VERSION 5.8 ;
BUSBITCHARS "[]" ;
DIVIDERCHAR "/" ;
UNITS
  DATABASE MICRONS 1000 ;
END UNITS
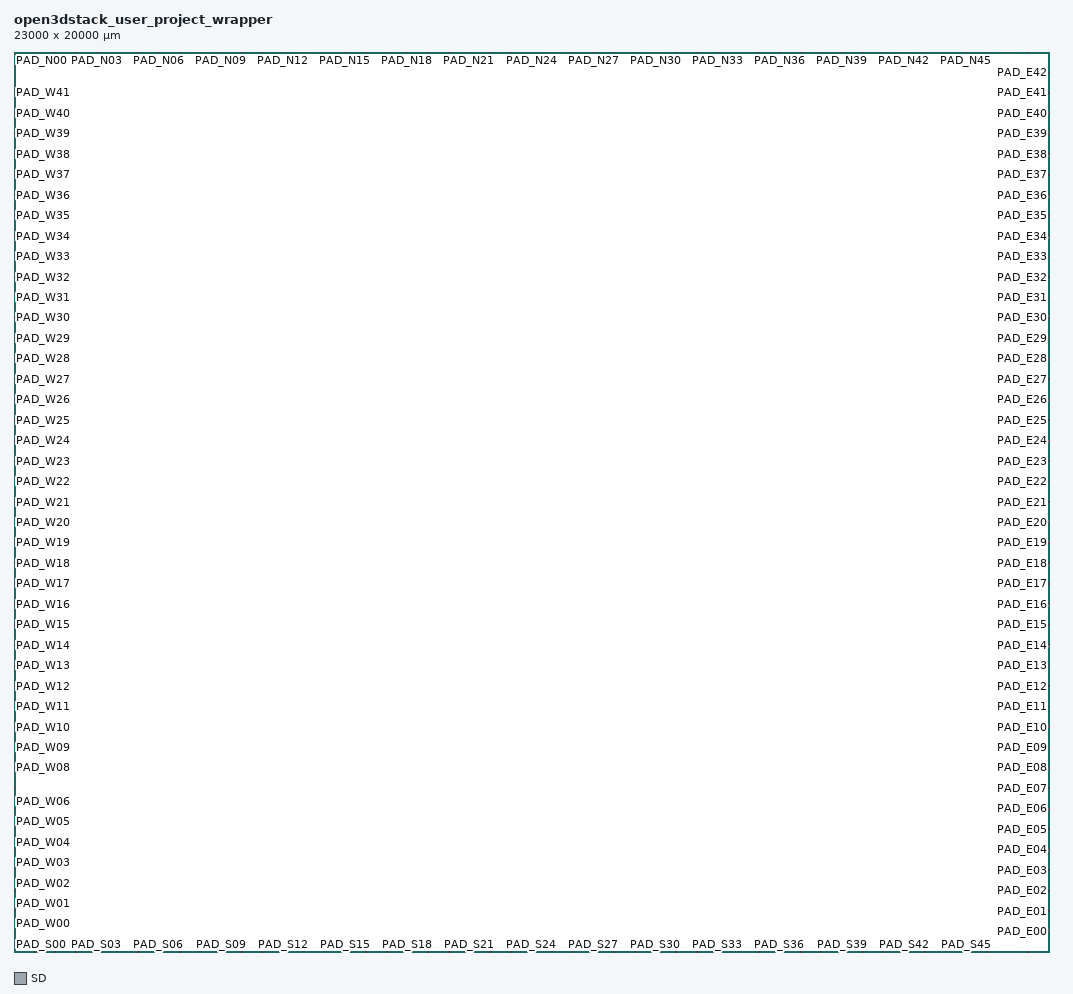
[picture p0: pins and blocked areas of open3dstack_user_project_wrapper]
MACRO open3dstack_user_project_wrapper
  CLASS BLOCK ;
  ORIGIN 0 0 ;
  FOREIGN open3dstack_user_project_wrapper 0 0 ;
  SIZE 23000 BY 20000 ;
  SYMMETRY X Y ;
  PIN PAD_S00
    DIRECTION INOUT ;
    USE SIGNAL ;
    PORT
      LAYER SD ;
        RECT 450 0 470 20 ;
    END
  END PAD_S00
  PIN PAD_S01
    DIRECTION INOUT ;
    USE SIGNAL ;
    PORT
      LAYER SD ;
        RECT 910 0 930 20 ;
    END
  END PAD_S01
  PIN PAD_S02
    DIRECTION INOUT ;
    USE SIGNAL ;
    PORT
      LAYER SD ;
        RECT 1370 0 1390 20 ;
    END
  END PAD_S02
  PIN PAD_S03
    DIRECTION INOUT ;
    USE SIGNAL ;
    PORT
      LAYER SD ;
        RECT 1830 0 1850 20 ;
    END
  END PAD_S03
  PIN PAD_S04
    DIRECTION INOUT ;
    USE SIGNAL ;
    PORT
      LAYER SD ;
        RECT 2290 0 2310 20 ;
    END
  END PAD_S04
  PIN PAD_S05
    DIRECTION INOUT ;
    USE SIGNAL ;
    PORT
      LAYER SD ;
        RECT 2750 0 2770 20 ;
    END
  END PAD_S05
  PIN PAD_S06
    DIRECTION INOUT ;
    USE SIGNAL ;
    PORT
      LAYER SD ;
        RECT 3210 0 3230 20 ;
    END
  END PAD_S06
  PIN PAD_S07
    DIRECTION INOUT ;
    USE SIGNAL ;
    PORT
      LAYER SD ;
        RECT 3670 0 3690 20 ;
    END
  END PAD_S07
  PIN PAD_S08
    DIRECTION INOUT ;
    USE SIGNAL ;
    PORT
      LAYER SD ;
        RECT 4130 0 4150 20 ;
    END
  END PAD_S08
  PIN PAD_S09
    DIRECTION INOUT ;
    USE SIGNAL ;
    PORT
      LAYER SD ;
        RECT 4590 0 4610 20 ;
    END
  END PAD_S09
  PIN PAD_S10
    DIRECTION INOUT ;
    USE SIGNAL ;
    PORT
      LAYER SD ;
        RECT 5050 0 5070 20 ;
    END
  END PAD_S10
  PIN PAD_S11
    DIRECTION INOUT ;
    USE SIGNAL ;
    PORT
      LAYER SD ;
        RECT 5510 0 5530 20 ;
    END
  END PAD_S11
  PIN PAD_S12
    DIRECTION INOUT ;
    USE SIGNAL ;
    PORT
      LAYER SD ;
        RECT 5970 0 5990 20 ;
    END
  END PAD_S12
  PIN PAD_S13
    DIRECTION INOUT ;
    USE SIGNAL ;
    PORT
      LAYER SD ;
        RECT 6430 0 6450 20 ;
    END
  END PAD_S13
  PIN PAD_S14
    DIRECTION INOUT ;
    USE SIGNAL ;
    PORT
      LAYER SD ;
        RECT 6890 0 6910 20 ;
    END
  END PAD_S14
  PIN PAD_S15
    DIRECTION INOUT ;
    USE SIGNAL ;
    PORT
      LAYER SD ;
        RECT 7350 0 7370 20 ;
    END
  END PAD_S15
  PIN PAD_S16
    DIRECTION INOUT ;
    USE SIGNAL ;
    PORT
      LAYER SD ;
        RECT 7810 0 7830 20 ;
    END
  END PAD_S16
  PIN PAD_S17
    DIRECTION INOUT ;
    USE SIGNAL ;
    PORT
      LAYER SD ;
        RECT 8270 0 8290 20 ;
    END
  END PAD_S17
  PIN PAD_S18
    DIRECTION INOUT ;
    USE SIGNAL ;
    PORT
      LAYER SD ;
        RECT 8730 0 8750 20 ;
    END
  END PAD_S18
  PIN PAD_S19
    DIRECTION INOUT ;
    USE SIGNAL ;
    PORT
      LAYER SD ;
        RECT 9190 0 9210 20 ;
    END
  END PAD_S19
  PIN PAD_S20
    DIRECTION INOUT ;
    USE SIGNAL ;
    PORT
      LAYER SD ;
        RECT 9650 0 9670 20 ;
    END
  END PAD_S20
  PIN PAD_S21
    DIRECTION INOUT ;
    USE SIGNAL ;
    PORT
      LAYER SD ;
        RECT 10110 0 10130 20 ;
    END
  END PAD_S21
  PIN PAD_S22
    DIRECTION INOUT ;
    USE SIGNAL ;
    PORT
      LAYER SD ;
        RECT 10570 0 10590 20 ;
    END
  END PAD_S22
  PIN PAD_S23
    DIRECTION INOUT ;
    USE SIGNAL ;
    PORT
      LAYER SD ;
        RECT 11030 0 11050 20 ;
    END
  END PAD_S23
  PIN PAD_S24
    DIRECTION INOUT ;
    USE SIGNAL ;
    PORT
      LAYER SD ;
        RECT 11490 0 11510 20 ;
    END
  END PAD_S24
  PIN PAD_S25
    DIRECTION INOUT ;
    USE SIGNAL ;
    PORT
      LAYER SD ;
        RECT 11950 0 11970 20 ;
    END
  END PAD_S25
  PIN PAD_S26
    DIRECTION INOUT ;
    USE SIGNAL ;
    PORT
      LAYER SD ;
        RECT 12410 0 12430 20 ;
    END
  END PAD_S26
  PIN PAD_S27
    DIRECTION INOUT ;
    USE SIGNAL ;
    PORT
      LAYER SD ;
        RECT 12870 0 12890 20 ;
    END
  END PAD_S27
  PIN PAD_S28
    DIRECTION INOUT ;
    USE SIGNAL ;
    PORT
      LAYER SD ;
        RECT 13330 0 13350 20 ;
    END
  END PAD_S28
  PIN PAD_S29
    DIRECTION INOUT ;
    USE SIGNAL ;
    PORT
      LAYER SD ;
        RECT 13790 0 13810 20 ;
    END
  END PAD_S29
  PIN PAD_S30
    DIRECTION INOUT ;
    USE SIGNAL ;
    PORT
      LAYER SD ;
        RECT 14250 0 14270 20 ;
    END
  END PAD_S30
  PIN PAD_S31
    DIRECTION INOUT ;
    USE SIGNAL ;
    PORT
      LAYER SD ;
        RECT 14710 0 14730 20 ;
    END
  END PAD_S31
  PIN PAD_S32
    DIRECTION INOUT ;
    USE SIGNAL ;
    PORT
      LAYER SD ;
        RECT 15170 0 15190 20 ;
    END
  END PAD_S32
  PIN PAD_S33
    DIRECTION INOUT ;
    USE SIGNAL ;
    PORT
      LAYER SD ;
        RECT 15630 0 15650 20 ;
    END
  END PAD_S33
  PIN PAD_S34
    DIRECTION INOUT ;
    USE SIGNAL ;
    PORT
      LAYER SD ;
        RECT 16090 0 16110 20 ;
    END
  END PAD_S34
  PIN PAD_S35
    DIRECTION INOUT ;
    USE SIGNAL ;
    PORT
      LAYER SD ;
        RECT 16550 0 16570 20 ;
    END
  END PAD_S35
  PIN PAD_S36
    DIRECTION INOUT ;
    USE SIGNAL ;
    PORT
      LAYER SD ;
        RECT 17010 0 17030 20 ;
    END
  END PAD_S36
  PIN PAD_S37
    DIRECTION INOUT ;
    USE SIGNAL ;
    PORT
      LAYER SD ;
        RECT 17470 0 17490 20 ;
    END
  END PAD_S37
  PIN PAD_S38
    DIRECTION INOUT ;
    USE SIGNAL ;
    PORT
      LAYER SD ;
        RECT 17930 0 17950 20 ;
    END
  END PAD_S38
  PIN PAD_S39
    DIRECTION INOUT ;
    USE SIGNAL ;
    PORT
      LAYER SD ;
        RECT 18390 0 18410 20 ;
    END
  END PAD_S39
  PIN PAD_S40
    DIRECTION INOUT ;
    USE SIGNAL ;
    PORT
      LAYER SD ;
        RECT 18850 0 18870 20 ;
    END
  END PAD_S40
  PIN PAD_S41
    DIRECTION INOUT ;
    USE SIGNAL ;
    PORT
      LAYER SD ;
        RECT 19310 0 19330 20 ;
    END
  END PAD_S41
  PIN PAD_S42
    DIRECTION INOUT ;
    USE SIGNAL ;
    PORT
      LAYER SD ;
        RECT 19770 0 19790 20 ;
    END
  END PAD_S42
  PIN PAD_S43
    DIRECTION INOUT ;
    USE SIGNAL ;
    PORT
      LAYER SD ;
        RECT 20230 0 20250 20 ;
    END
  END PAD_S43
  PIN PAD_S44
    DIRECTION INOUT ;
    USE SIGNAL ;
    PORT
      LAYER SD ;
        RECT 20690 0 20710 20 ;
    END
  END PAD_S44
  PIN PAD_S45
    DIRECTION INOUT ;
    USE SIGNAL ;
    PORT
      LAYER SD ;
        RECT 21150 0 21170 20 ;
    END
  END PAD_S45
  PIN PAD_S46
    DIRECTION INOUT ;
    USE SIGNAL ;
    PORT
      LAYER SD ;
        RECT 21610 0 21630 20 ;
    END
  END PAD_S46
  PIN PAD_S47
    DIRECTION INOUT ;
    USE SIGNAL ;
    PORT
      LAYER SD ;
        RECT 22070 0 22090 20 ;
    END
  END PAD_S47
  PIN PAD_S48
    DIRECTION INOUT ;
    USE SIGNAL ;
    PORT
      LAYER SD ;
        RECT 22530 0 22550 20 ;
    END
  END PAD_S48
  PIN PAD_E00
    DIRECTION INOUT ;
    USE SIGNAL ;
    PORT
      LAYER SD ;
        RECT 22980 444.545 23000 464.545 ;
    END
  END PAD_E00
  PIN PAD_E01
    DIRECTION INOUT ;
    USE SIGNAL ;
    PORT
      LAYER SD ;
        RECT 22980 899.091 23000 919.091 ;
    END
  END PAD_E01
  PIN PAD_E02
    DIRECTION INOUT ;
    USE SIGNAL ;
    PORT
      LAYER SD ;
        RECT 22980 1353.636 23000 1373.636 ;
    END
  END PAD_E02
  PIN PAD_E03
    DIRECTION INOUT ;
    USE SIGNAL ;
    PORT
      LAYER SD ;
        RECT 22980 1808.182 23000 1828.182 ;
    END
  END PAD_E03
  PIN PAD_E04
    DIRECTION INOUT ;
    USE SIGNAL ;
    PORT
      LAYER SD ;
        RECT 22980 2262.727 23000 2282.727 ;
    END
  END PAD_E04
  PIN PAD_E05
    DIRECTION INOUT ;
    USE SIGNAL ;
    PORT
      LAYER SD ;
        RECT 22980 2717.273 23000 2737.273 ;
    END
  END PAD_E05
  PIN PAD_E06
    DIRECTION INOUT ;
    USE SIGNAL ;
    PORT
      LAYER SD ;
        RECT 22980 3171.818 23000 3191.818 ;
    END
  END PAD_E06
  PIN PAD_E07
    DIRECTION INOUT ;
    USE SIGNAL ;
    PORT
      LAYER SD ;
        RECT 22980 3626.364 23000 3646.364 ;
    END
  END PAD_E07
  PIN PAD_E08
    DIRECTION INOUT ;
    USE SIGNAL ;
    PORT
      LAYER SD ;
        RECT 22980 4080.909 23000 4100.909 ;
    END
  END PAD_E08
  PIN PAD_E09
    DIRECTION INOUT ;
    USE SIGNAL ;
    PORT
      LAYER SD ;
        RECT 22980 4535.455 23000 4555.455 ;
    END
  END PAD_E09
  PIN PAD_E10
    DIRECTION INOUT ;
    USE SIGNAL ;
    PORT
      LAYER SD ;
        RECT 22980 4990 23000 5010 ;
    END
  END PAD_E10
  PIN PAD_E11
    DIRECTION INOUT ;
    USE SIGNAL ;
    PORT
      LAYER SD ;
        RECT 22980 5444.545 23000 5464.545 ;
    END
  END PAD_E11
  PIN PAD_E12
    DIRECTION INOUT ;
    USE SIGNAL ;
    PORT
      LAYER SD ;
        RECT 22980 5899.091 23000 5919.091 ;
    END
  END PAD_E12
  PIN PAD_E13
    DIRECTION INOUT ;
    USE SIGNAL ;
    PORT
      LAYER SD ;
        RECT 22980 6353.636 23000 6373.636 ;
    END
  END PAD_E13
  PIN PAD_E14
    DIRECTION INOUT ;
    USE SIGNAL ;
    PORT
      LAYER SD ;
        RECT 22980 6808.182 23000 6828.182 ;
    END
  END PAD_E14
  PIN PAD_E15
    DIRECTION INOUT ;
    USE SIGNAL ;
    PORT
      LAYER SD ;
        RECT 22980 7262.727 23000 7282.727 ;
    END
  END PAD_E15
  PIN PAD_E16
    DIRECTION INOUT ;
    USE SIGNAL ;
    PORT
      LAYER SD ;
        RECT 22980 7717.273 23000 7737.273 ;
    END
  END PAD_E16
  PIN PAD_E17
    DIRECTION INOUT ;
    USE SIGNAL ;
    PORT
      LAYER SD ;
        RECT 22980 8171.818 23000 8191.818 ;
    END
  END PAD_E17
  PIN PAD_E18
    DIRECTION INOUT ;
    USE SIGNAL ;
    PORT
      LAYER SD ;
        RECT 22980 8626.364 23000 8646.364 ;
    END
  END PAD_E18
  PIN PAD_E19
    DIRECTION INOUT ;
    USE SIGNAL ;
    PORT
      LAYER SD ;
        RECT 22980 9080.909 23000 9100.909 ;
    END
  END PAD_E19
  PIN PAD_E20
    DIRECTION INOUT ;
    USE SIGNAL ;
    PORT
      LAYER SD ;
        RECT 22980 9535.455 23000 9555.455 ;
    END
  END PAD_E20
  PIN PAD_E21
    DIRECTION INOUT ;
    USE SIGNAL ;
    PORT
      LAYER SD ;
        RECT 22980 9990 23000 10010 ;
    END
  END PAD_E21
  PIN PAD_E22
    DIRECTION INOUT ;
    USE SIGNAL ;
    PORT
      LAYER SD ;
        RECT 22980 10444.545 23000 10464.545 ;
    END
  END PAD_E22
  PIN PAD_E23
    DIRECTION INOUT ;
    USE SIGNAL ;
    PORT
      LAYER SD ;
        RECT 22980 10899.091 23000 10919.091 ;
    END
  END PAD_E23
  PIN PAD_E24
    DIRECTION INOUT ;
    USE SIGNAL ;
    PORT
      LAYER SD ;
        RECT 22980 11353.636 23000 11373.636 ;
    END
  END PAD_E24
  PIN PAD_E25
    DIRECTION INOUT ;
    USE SIGNAL ;
    PORT
      LAYER SD ;
        RECT 22980 11808.182 23000 11828.182 ;
    END
  END PAD_E25
  PIN PAD_E26
    DIRECTION INOUT ;
    USE SIGNAL ;
    PORT
      LAYER SD ;
        RECT 22980 12262.727 23000 12282.727 ;
    END
  END PAD_E26
  PIN PAD_E27
    DIRECTION INOUT ;
    USE SIGNAL ;
    PORT
      LAYER SD ;
        RECT 22980 12717.273 23000 12737.273 ;
    END
  END PAD_E27
  PIN PAD_E28
    DIRECTION INOUT ;
    USE SIGNAL ;
    PORT
      LAYER SD ;
        RECT 22980 13171.818 23000 13191.818 ;
    END
  END PAD_E28
  PIN PAD_E29
    DIRECTION INOUT ;
    USE SIGNAL ;
    PORT
      LAYER SD ;
        RECT 22980 13626.364 23000 13646.364 ;
    END
  END PAD_E29
  PIN PAD_E30
    DIRECTION INOUT ;
    USE SIGNAL ;
    PORT
      LAYER SD ;
        RECT 22980 14080.909 23000 14100.909 ;
    END
  END PAD_E30
  PIN PAD_E31
    DIRECTION INOUT ;
    USE SIGNAL ;
    PORT
      LAYER SD ;
        RECT 22980 14535.455 23000 14555.455 ;
    END
  END PAD_E31
  PIN PAD_E32
    DIRECTION INOUT ;
    USE SIGNAL ;
    PORT
      LAYER SD ;
        RECT 22980 14990 23000 15010 ;
    END
  END PAD_E32
  PIN PAD_E33
    DIRECTION INOUT ;
    USE SIGNAL ;
    PORT
      LAYER SD ;
        RECT 22980 15444.545 23000 15464.545 ;
    END
  END PAD_E33
  PIN PAD_E34
    DIRECTION INOUT ;
    USE SIGNAL ;
    PORT
      LAYER SD ;
        RECT 22980 15899.091 23000 15919.091 ;
    END
  END PAD_E34
  PIN PAD_E35
    DIRECTION INOUT ;
    USE SIGNAL ;
    PORT
      LAYER SD ;
        RECT 22980 16353.636 23000 16373.636 ;
    END
  END PAD_E35
  PIN PAD_E36
    DIRECTION INOUT ;
    USE SIGNAL ;
    PORT
      LAYER SD ;
        RECT 22980 16808.182 23000 16828.182 ;
    END
  END PAD_E36
  PIN PAD_E37
    DIRECTION INOUT ;
    USE SIGNAL ;
    PORT
      LAYER SD ;
        RECT 22980 17262.727 23000 17282.727 ;
    END
  END PAD_E37
  PIN PAD_E38
    DIRECTION INOUT ;
    USE SIGNAL ;
    PORT
      LAYER SD ;
        RECT 22980 17717.273 23000 17737.273 ;
    END
  END PAD_E38
  PIN PAD_E39
    DIRECTION INOUT ;
    USE SIGNAL ;
    PORT
      LAYER SD ;
        RECT 22980 18171.818 23000 18191.818 ;
    END
  END PAD_E39
  PIN PAD_E40
    DIRECTION INOUT ;
    USE SIGNAL ;
    PORT
      LAYER SD ;
        RECT 22980 18626.364 23000 18646.364 ;
    END
  END PAD_E40
  PIN PAD_E41
    DIRECTION INOUT ;
    USE SIGNAL ;
    PORT
      LAYER SD ;
        RECT 22980 19080.909 23000 19100.909 ;
    END
  END PAD_E41
  PIN PAD_E42
    DIRECTION INOUT ;
    USE SIGNAL ;
    PORT
      LAYER SD ;
        RECT 22980 19535.455 23000 19555.455 ;
    END
  END PAD_E42
  PIN PAD_N00
    DIRECTION INOUT ;
    USE SIGNAL ;
    PORT
      LAYER SD ;
        RECT 450 19980 470 20000 ;
    END
  END PAD_N00
  PIN PAD_N01
    DIRECTION INOUT ;
    USE SIGNAL ;
    PORT
      LAYER SD ;
        RECT 910 19980 930 20000 ;
    END
  END PAD_N01
  PIN PAD_N02
    DIRECTION INOUT ;
    USE SIGNAL ;
    PORT
      LAYER SD ;
        RECT 1370 19980 1390 20000 ;
    END
  END PAD_N02
  PIN PAD_N03
    DIRECTION INOUT ;
    USE SIGNAL ;
    PORT
      LAYER SD ;
        RECT 1830 19980 1850 20000 ;
    END
  END PAD_N03
  PIN PAD_N04
    DIRECTION INOUT ;
    USE SIGNAL ;
    PORT
      LAYER SD ;
        RECT 2290 19980 2310 20000 ;
    END
  END PAD_N04
  PIN PAD_N05
    DIRECTION INOUT ;
    USE SIGNAL ;
    PORT
      LAYER SD ;
        RECT 2750 19980 2770 20000 ;
    END
  END PAD_N05
  PIN PAD_N06
    DIRECTION INOUT ;
    USE SIGNAL ;
    PORT
      LAYER SD ;
        RECT 3210 19980 3230 20000 ;
    END
  END PAD_N06
  PIN PAD_N07
    DIRECTION INOUT ;
    USE SIGNAL ;
    PORT
      LAYER SD ;
        RECT 3670 19980 3690 20000 ;
    END
  END PAD_N07
  PIN PAD_N08
    DIRECTION INOUT ;
    USE SIGNAL ;
    PORT
      LAYER SD ;
        RECT 4130 19980 4150 20000 ;
    END
  END PAD_N08
  PIN PAD_N09
    DIRECTION INOUT ;
    USE SIGNAL ;
    PORT
      LAYER SD ;
        RECT 4590 19980 4610 20000 ;
    END
  END PAD_N09
  PIN PAD_N10
    DIRECTION INOUT ;
    USE SIGNAL ;
    PORT
      LAYER SD ;
        RECT 5050 19980 5070 20000 ;
    END
  END PAD_N10
  PIN PAD_N11
    DIRECTION INOUT ;
    USE SIGNAL ;
    PORT
      LAYER SD ;
        RECT 5510 19980 5530 20000 ;
    END
  END PAD_N11
  PIN PAD_N12
    DIRECTION INOUT ;
    USE SIGNAL ;
    PORT
      LAYER SD ;
        RECT 5970 19980 5990 20000 ;
    END
  END PAD_N12
  PIN PAD_N13
    DIRECTION INOUT ;
    USE SIGNAL ;
    PORT
      LAYER SD ;
        RECT 6430 19980 6450 20000 ;
    END
  END PAD_N13
  PIN PAD_N14
    DIRECTION INOUT ;
    USE SIGNAL ;
    PORT
      LAYER SD ;
        RECT 6890 19980 6910 20000 ;
    END
  END PAD_N14
  PIN PAD_N15
    DIRECTION INOUT ;
    USE SIGNAL ;
    PORT
      LAYER SD ;
        RECT 7350 19980 7370 20000 ;
    END
  END PAD_N15
  PIN PAD_N16
    DIRECTION INOUT ;
    USE SIGNAL ;
    PORT
      LAYER SD ;
        RECT 7810 19980 7830 20000 ;
    END
  END PAD_N16
  PIN PAD_N17
    DIRECTION INOUT ;
    USE SIGNAL ;
    PORT
      LAYER SD ;
        RECT 8270 19980 8290 20000 ;
    END
  END PAD_N17
  PIN PAD_N18
    DIRECTION INOUT ;
    USE SIGNAL ;
    PORT
      LAYER SD ;
        RECT 8730 19980 8750 20000 ;
    END
  END PAD_N18
  PIN PAD_N19
    DIRECTION INOUT ;
    USE SIGNAL ;
    PORT
      LAYER SD ;
        RECT 9190 19980 9210 20000 ;
    END
  END PAD_N19
  PIN PAD_N20
    DIRECTION INOUT ;
    USE SIGNAL ;
    PORT
      LAYER SD ;
        RECT 9650 19980 9670 20000 ;
    END
  END PAD_N20
  PIN PAD_N21
    DIRECTION INOUT ;
    USE SIGNAL ;
    PORT
      LAYER SD ;
        RECT 10110 19980 10130 20000 ;
    END
  END PAD_N21
  PIN PAD_N22
    DIRECTION INOUT ;
    USE SIGNAL ;
    PORT
      LAYER SD ;
        RECT 10570 19980 10590 20000 ;
    END
  END PAD_N22
  PIN PAD_N23
    DIRECTION INOUT ;
    USE SIGNAL ;
    PORT
      LAYER SD ;
        RECT 11030 19980 11050 20000 ;
    END
  END PAD_N23
  PIN PAD_N24
    DIRECTION INOUT ;
    USE SIGNAL ;
    PORT
      LAYER SD ;
        RECT 11490 19980 11510 20000 ;
    END
  END PAD_N24
  PIN PAD_N25
    DIRECTION INOUT ;
    USE SIGNAL ;
    PORT
      LAYER SD ;
        RECT 11950 19980 11970 20000 ;
    END
  END PAD_N25
  PIN PAD_N26
    DIRECTION INOUT ;
    USE SIGNAL ;
    PORT
      LAYER SD ;
        RECT 12410 19980 12430 20000 ;
    END
  END PAD_N26
  PIN PAD_N27
    DIRECTION INOUT ;
    USE SIGNAL ;
    PORT
      LAYER SD ;
        RECT 12870 19980 12890 20000 ;
    END
  END PAD_N27
  PIN PAD_N28
    DIRECTION INOUT ;
    USE SIGNAL ;
    PORT
      LAYER SD ;
        RECT 13330 19980 13350 20000 ;
    END
  END PAD_N28
  PIN PAD_N29
    DIRECTION INOUT ;
    USE SIGNAL ;
    PORT
      LAYER SD ;
        RECT 13790 19980 13810 20000 ;
    END
  END PAD_N29
  PIN PAD_N30
    DIRECTION INOUT ;
    USE SIGNAL ;
    PORT
      LAYER SD ;
        RECT 14250 19980 14270 20000 ;
    END
  END PAD_N30
  PIN PAD_N31
    DIRECTION INOUT ;
    USE SIGNAL ;
    PORT
      LAYER SD ;
        RECT 14710 19980 14730 20000 ;
    END
  END PAD_N31
  PIN PAD_N32
    DIRECTION INOUT ;
    USE SIGNAL ;
    PORT
      LAYER SD ;
        RECT 15170 19980 15190 20000 ;
    END
  END PAD_N32
  PIN PAD_N33
    DIRECTION INOUT ;
    USE SIGNAL ;
    PORT
      LAYER SD ;
        RECT 15630 19980 15650 20000 ;
    END
  END PAD_N33
  PIN PAD_N34
    DIRECTION INOUT ;
    USE SIGNAL ;
    PORT
      LAYER SD ;
        RECT 16090 19980 16110 20000 ;
    END
  END PAD_N34
  PIN PAD_N35
    DIRECTION INOUT ;
    USE SIGNAL ;
    PORT
      LAYER SD ;
        RECT 16550 19980 16570 20000 ;
    END
  END PAD_N35
  PIN PAD_N36
    DIRECTION INOUT ;
    USE SIGNAL ;
    PORT
      LAYER SD ;
        RECT 17010 19980 17030 20000 ;
    END
  END PAD_N36
  PIN PAD_N37
    DIRECTION INOUT ;
    USE SIGNAL ;
    PORT
      LAYER SD ;
        RECT 17470 19980 17490 20000 ;
    END
  END PAD_N37
  PIN PAD_N38
    DIRECTION INOUT ;
    USE SIGNAL ;
    PORT
      LAYER SD ;
        RECT 17930 19980 17950 20000 ;
    END
  END PAD_N38
  PIN PAD_N39
    DIRECTION INOUT ;
    USE SIGNAL ;
    PORT
      LAYER SD ;
        RECT 18390 19980 18410 20000 ;
    END
  END PAD_N39
  PIN PAD_N40
    DIRECTION INOUT ;
    USE SIGNAL ;
    PORT
      LAYER SD ;
        RECT 18850 19980 18870 20000 ;
    END
  END PAD_N40
  PIN PAD_N41
    DIRECTION INOUT ;
    USE SIGNAL ;
    PORT
      LAYER SD ;
        RECT 19310 19980 19330 20000 ;
    END
  END PAD_N41
  PIN PAD_N42
    DIRECTION INOUT ;
    USE SIGNAL ;
    PORT
      LAYER SD ;
        RECT 19770 19980 19790 20000 ;
    END
  END PAD_N42
  PIN PAD_N43
    DIRECTION INOUT ;
    USE SIGNAL ;
    PORT
      LAYER SD ;
        RECT 20230 19980 20250 20000 ;
    END
  END PAD_N43
  PIN PAD_N44
    DIRECTION INOUT ;
    USE SIGNAL ;
    PORT
      LAYER SD ;
        RECT 20690 19980 20710 20000 ;
    END
  END PAD_N44
  PIN PAD_N45
    DIRECTION INOUT ;
    USE SIGNAL ;
    PORT
      LAYER SD ;
        RECT 21150 19980 21170 20000 ;
    END
  END PAD_N45
  PIN PAD_N46
    DIRECTION INOUT ;
    USE SIGNAL ;
    PORT
      LAYER SD ;
        RECT 21610 19980 21630 20000 ;
    END
  END PAD_N46
  PIN PAD_N47
    DIRECTION INOUT ;
    USE SIGNAL ;
    PORT
      LAYER SD ;
        RECT 22070 19980 22090 20000 ;
    END
  END PAD_N47
  PIN PAD_N48
    DIRECTION INOUT ;
    USE SIGNAL ;
    PORT
      LAYER SD ;
        RECT 22530 19980 22550 20000 ;
    END
  END PAD_N48
  PIN PAD_W00
    DIRECTION INOUT ;
    USE SIGNAL ;
    PORT
      LAYER SD ;
        RECT 0 444.545 20 464.545 ;
    END
  END PAD_W00
  PIN PAD_W01
    DIRECTION INOUT ;
    USE SIGNAL ;
    PORT
      LAYER SD ;
        RECT 0 899.091 20 919.091 ;
    END
  END PAD_W01
  PIN PAD_W02
    DIRECTION INOUT ;
    USE SIGNAL ;
    PORT
      LAYER SD ;
        RECT 0 1353.636 20 1373.636 ;
    END
  END PAD_W02
  PIN PAD_W03
    DIRECTION INOUT ;
    USE SIGNAL ;
    PORT
      LAYER SD ;
        RECT 0 1808.182 20 1828.182 ;
    END
  END PAD_W03
  PIN PAD_W04
    DIRECTION INOUT ;
    USE SIGNAL ;
    PORT
      LAYER SD ;
        RECT 0 2262.727 20 2282.727 ;
    END
  END PAD_W04
  PIN PAD_W05
    DIRECTION INOUT ;
    USE SIGNAL ;
    PORT
      LAYER SD ;
        RECT 0 2717.273 20 2737.273 ;
    END
  END PAD_W05
  PIN PAD_W06
    DIRECTION INOUT ;
    USE SIGNAL ;
    PORT
      LAYER SD ;
        RECT 0 3171.818 20 3191.818 ;
    END
  END PAD_W06
  PIN PAD_W07
    DIRECTION INOUT ;
    USE SIGNAL ;
    PORT
      LAYER SD ;
        RECT 0 3626.364 20 3646.364 ;
    END
  END PAD_W07
  PIN PAD_W08
    DIRECTION INOUT ;
    USE SIGNAL ;
    PORT
      LAYER SD ;
        RECT 0 4080.909 20 4100.909 ;
    END
  END PAD_W08
  PIN PAD_W09
    DIRECTION INOUT ;
    USE SIGNAL ;
    PORT
      LAYER SD ;
        RECT 0 4535.455 20 4555.455 ;
    END
  END PAD_W09
  PIN PAD_W10
    DIRECTION INOUT ;
    USE SIGNAL ;
    PORT
      LAYER SD ;
        RECT 0 4990 20 5010 ;
    END
  END PAD_W10
  PIN PAD_W11
    DIRECTION INOUT ;
    USE SIGNAL ;
    PORT
      LAYER SD ;
        RECT 0 5444.545 20 5464.545 ;
    END
  END PAD_W11
  PIN PAD_W12
    DIRECTION INOUT ;
    USE SIGNAL ;
    PORT
      LAYER SD ;
        RECT 0 5899.091 20 5919.091 ;
    END
  END PAD_W12
  PIN PAD_W13
    DIRECTION INOUT ;
    USE SIGNAL ;
    PORT
      LAYER SD ;
        RECT 0 6353.636 20 6373.636 ;
    END
  END PAD_W13
  PIN PAD_W14
    DIRECTION INOUT ;
    USE SIGNAL ;
    PORT
      LAYER SD ;
        RECT 0 6808.182 20 6828.182 ;
    END
  END PAD_W14
  PIN PAD_W15
    DIRECTION INOUT ;
    USE SIGNAL ;
    PORT
      LAYER SD ;
        RECT 0 7262.727 20 7282.727 ;
    END
  END PAD_W15
  PIN PAD_W16
    DIRECTION INOUT ;
    USE SIGNAL ;
    PORT
      LAYER SD ;
        RECT 0 7717.273 20 7737.273 ;
    END
  END PAD_W16
  PIN PAD_W17
    DIRECTION INOUT ;
    USE SIGNAL ;
    PORT
      LAYER SD ;
        RECT 0 8171.818 20 8191.818 ;
    END
  END PAD_W17
  PIN PAD_W18
    DIRECTION INOUT ;
    USE SIGNAL ;
    PORT
      LAYER SD ;
        RECT 0 8626.364 20 8646.364 ;
    END
  END PAD_W18
  PIN PAD_W19
    DIRECTION INOUT ;
    USE SIGNAL ;
    PORT
      LAYER SD ;
        RECT 0 9080.909 20 9100.909 ;
    END
  END PAD_W19
  PIN PAD_W20
    DIRECTION INOUT ;
    USE SIGNAL ;
    PORT
      LAYER SD ;
        RECT 0 9535.455 20 9555.455 ;
    END
  END PAD_W20
  PIN PAD_W21
    DIRECTION INOUT ;
    USE SIGNAL ;
    PORT
      LAYER SD ;
        RECT 0 9990 20 10010 ;
    END
  END PAD_W21
  PIN PAD_W22
    DIRECTION INOUT ;
    USE SIGNAL ;
    PORT
      LAYER SD ;
        RECT 0 10444.545 20 10464.545 ;
    END
  END PAD_W22
  PIN PAD_W23
    DIRECTION INOUT ;
    USE SIGNAL ;
    PORT
      LAYER SD ;
        RECT 0 10899.091 20 10919.091 ;
    END
  END PAD_W23
  PIN PAD_W24
    DIRECTION INOUT ;
    USE SIGNAL ;
    PORT
      LAYER SD ;
        RECT 0 11353.636 20 11373.636 ;
    END
  END PAD_W24
  PIN PAD_W25
    DIRECTION INOUT ;
    USE SIGNAL ;
    PORT
      LAYER SD ;
        RECT 0 11808.182 20 11828.182 ;
    END
  END PAD_W25
  PIN PAD_W26
    DIRECTION INOUT ;
    USE SIGNAL ;
    PORT
      LAYER SD ;
        RECT 0 12262.727 20 12282.727 ;
    END
  END PAD_W26
  PIN PAD_W27
    DIRECTION INOUT ;
    USE SIGNAL ;
    PORT
      LAYER SD ;
        RECT 0 12717.273 20 12737.273 ;
    END
  END PAD_W27
  PIN PAD_W28
    DIRECTION INOUT ;
    USE SIGNAL ;
    PORT
      LAYER SD ;
        RECT 0 13171.818 20 13191.818 ;
    END
  END PAD_W28
  PIN PAD_W29
    DIRECTION INOUT ;
    USE SIGNAL ;
    PORT
      LAYER SD ;
        RECT 0 13626.364 20 13646.364 ;
    END
  END PAD_W29
  PIN PAD_W30
    DIRECTION INOUT ;
    USE SIGNAL ;
    PORT
      LAYER SD ;
        RECT 0 14080.909 20 14100.909 ;
    END
  END PAD_W30
  PIN PAD_W31
    DIRECTION INOUT ;
    USE SIGNAL ;
    PORT
      LAYER SD ;
        RECT 0 14535.455 20 14555.455 ;
    END
  END PAD_W31
  PIN PAD_W32
    DIRECTION INOUT ;
    USE SIGNAL ;
    PORT
      LAYER SD ;
        RECT 0 14990 20 15010 ;
    END
  END PAD_W32
  PIN PAD_W33
    DIRECTION INOUT ;
    USE SIGNAL ;
    PORT
      LAYER SD ;
        RECT 0 15444.545 20 15464.545 ;
    END
  END PAD_W33
  PIN PAD_W34
    DIRECTION INOUT ;
    USE SIGNAL ;
    PORT
      LAYER SD ;
        RECT 0 15899.091 20 15919.091 ;
    END
  END PAD_W34
  PIN PAD_W35
    DIRECTION INOUT ;
    USE SIGNAL ;
    PORT
      LAYER SD ;
        RECT 0 16353.636 20 16373.636 ;
    END
  END PAD_W35
  PIN PAD_W36
    DIRECTION INOUT ;
    USE SIGNAL ;
    PORT
      LAYER SD ;
        RECT 0 16808.182 20 16828.182 ;
    END
  END PAD_W36
  PIN PAD_W37
    DIRECTION INOUT ;
    USE SIGNAL ;
    PORT
      LAYER SD ;
        RECT 0 17262.727 20 17282.727 ;
    END
  END PAD_W37
  PIN PAD_W38
    DIRECTION INOUT ;
    USE SIGNAL ;
    PORT
      LAYER SD ;
        RECT 0 17717.273 20 17737.273 ;
    END
  END PAD_W38
  PIN PAD_W39
    DIRECTION INOUT ;
    USE SIGNAL ;
    PORT
      LAYER SD ;
        RECT 0 18171.818 20 18191.818 ;
    END
  END PAD_W39
  PIN PAD_W40
    DIRECTION INOUT ;
    USE SIGNAL ;
    PORT
      LAYER SD ;
        RECT 0 18626.364 20 18646.364 ;
    END
  END PAD_W40
  PIN PAD_W41
    DIRECTION INOUT ;
    USE SIGNAL ;
    PORT
      LAYER SD ;
        RECT 0 19080.909 20 19100.909 ;
    END
  END PAD_W41
  PIN PAD_W42
    DIRECTION INOUT ;
    USE SIGNAL ;
    PORT
      LAYER SD ;
        RECT 0 19535.455 20 19555.455 ;
    END
  END PAD_W42
END open3dstack_user_project_wrapper
END LIBRARY
